VERSION 5.8 ;
BUSBITCHARS "[]" ;
DIVIDERCHAR "/" ;
UNITS
  DATABASE MICRONS 1000 ;
END UNITS
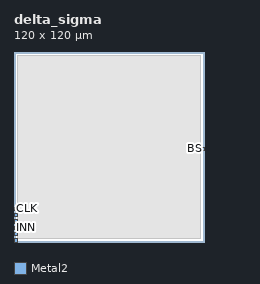
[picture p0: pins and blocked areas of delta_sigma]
MACRO delta_sigma
  CLASS BLOCK ;
  ORIGIN 0 0 ;
  FOREIGN delta_sigma 0 0 ;
  SIZE 120.000 BY 120.000 ;
  SYMMETRY X Y R90 ;
  PIN VDD   DIRECTION INOUT ; USE POWER  ; PORT LAYER Metal2 ; RECT 0 0 2 2 ; END END VDD
  PIN VSS   DIRECTION INOUT ; USE GROUND ; PORT LAYER Metal2 ; RECT 0 4 2 6 ; END END VSS
  PIN INP   DIRECTION INPUT ; USE SIGNAL ; PORT LAYER Metal2 ; RECT 0 8 2 10 ; END END INP
  PIN INN   DIRECTION INPUT ; USE SIGNAL ; PORT LAYER Metal2 ; RECT 0 12 2 14 ; END END INN
  PIN VREF  DIRECTION INPUT ; USE SIGNAL ; PORT LAYER Metal2 ; RECT 0 16 2 18 ; END END VREF
  PIN CLK   DIRECTION INPUT ; USE SIGNAL ; PORT LAYER Metal2 ; RECT 0 20 2 22 ; END END CLK
  PIN BS    DIRECTION OUTPUT; USE SIGNAL ; PORT LAYER Metal2 ; RECT 118 58 120 60 ; END END BS
  OBS LAYER Metal1 ; RECT 2 2 118 118 ; END
END delta_sigma
END LIBRARY
